VERSION 5.8 ;
BUSBITCHARS "<>" ;
DIVIDERCHAR "/" ;

UNITS
   DATABASE MICRONS 1000 ;
END UNITS

PROPERTYDEFINITIONS
   MACRO cell_kind STRING ;
END PROPERTYDEFINITIONS

LAYER M1
   TYPE ROUTING ;
   DIRECTION HORIZONTAL ;
   PITCH 0.2 ;
   WIDTH 0.1 ;
END M1

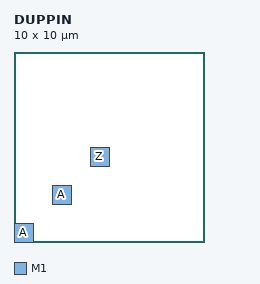
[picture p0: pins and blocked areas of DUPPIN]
MACRO DUPPIN
   CLASS CORE ;
   SIZE 10 BY 10 ;
   PIN A
      DIRECTION INPUT ;
      PORT
         LAYER M1 ;
            RECT 0 0 1 1 ;
      END
   END A
   PIN A
      DIRECTION OUTPUT ;
      ANTENNAMODEL OXIDE1 ;
      ANTENNAGATEAREA 1.0 ;
      PORT
         LAYER M1 ;
            RECT 2 2 3 3 ;
      END
   END A
   PIN Z
      DIRECTION OUTPUT ;
      PORT
         LAYER M1 ;
            RECT 4 4 5 5 ;
      END
   END Z
END DUPPIN

END LIBRARY
